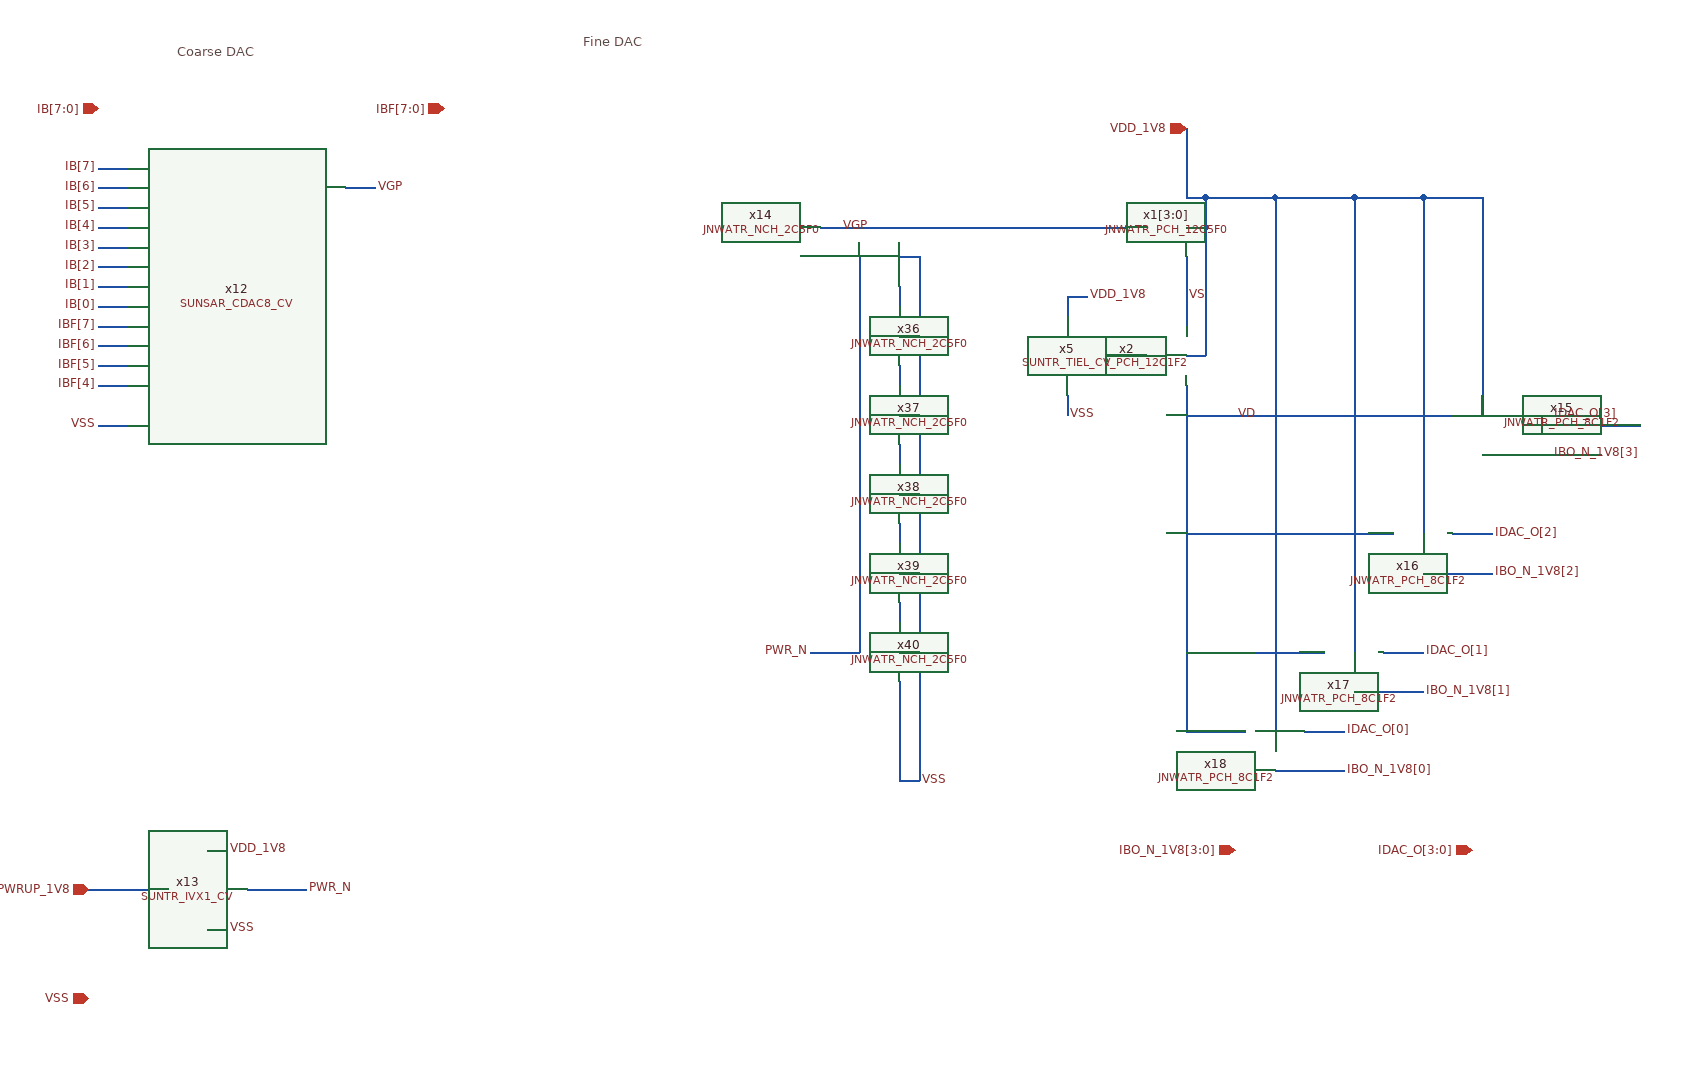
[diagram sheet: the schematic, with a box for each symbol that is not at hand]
v {xschem version=3.4.5 file_version=1.2
}
G {}
K {}
V {}
S {}
E {}
T {Coarse DAC} 1280 -1430 0 0 0.4 0.4 {}
T {Fine DAC} 1690 -1440 0 0 0.4 0.4 {}
N 2300 -1210 2300 -1140 {
lab=VS}
N 2300 -1110 2320 -1110 {
lab=VDD_1V8}
N 2320 -1240 2320 -1110 {
lab=VDD_1V8}
N 2300 -1240 2320 -1240 {
lab=VDD_1V8}
N 2320 -1270 2320 -1240 {
lab=VDD_1V8}
N 2300 -1270 2320 -1270 {
lab=VDD_1V8}
N 2300 -1330 2300 -1270 {
lab=VDD_1V8}
N 1930 -1240 2260 -1240 {
lab=VGP}
N 2300 -1080 2300 -900 {
lab=VD}
N 1310 -610 1330 -610 {
lab=VDD_1V8}
N 1310 -530 1330 -530 {
lab=VSS}
N 1250 -570 1270 -570 {
lab=PWRUP_1V8}
N 1190 -570 1250 -570 {
lab=PWRUP_1V8}
N 1350 -570 1410 -570 {
lab=PWR_N}
N 2390 -1270 2390 -730 {
lab=VDD_1V8}
N 2320 -1270 2390 -1270 {
lab=VDD_1V8}
N 2470 -1270 2470 -810 {
lab=VDD_1V8}
N 2390 -1270 2470 -1270 {
lab=VDD_1V8}
N 2470 -1270 2540 -1270 {
lab=VDD_1V8}
N 2600 -1270 2600 -1050 {
lab=VDD_1V8}
N 2540 -1270 2600 -1270 {
lab=VDD_1V8}
N 2300 -1050 2570 -1050 {
lab=VD}
N 2300 -900 2300 -730 {
lab=VD}
N 2300 -730 2360 -730 {
lab=VD}
N 2300 -810 2440 -810 {
lab=VD}
N 2300 -930 2510 -930 {
lab=VD}
N 2540 -1270 2540 -930 {
lab=VDD_1V8}
N 2630 -1050 2670 -1050 {
lab=IDAC_O[3]}
N 2570 -930 2610 -930 {
lab=IDAC_O[2]}
N 2500 -810 2540 -810 {
lab=IDAC_O[1]}
N 2420 -730 2460 -730 {
lab=IDAC_O[0]}
N 2390 -690 2460 -690 {
lab=IBO_N_1V8[0]}
N 2470 -770 2540 -770 {
lab=IBO_N_1V8[1]}
N 2540 -890 2610 -890 {
lab=IBO_N_1V8[2]}
N 2600 -1010 2670 -1010 {
lab=IBO_N_1V8[3]}
N 1200 -1160 1230 -1160 {
lab=IB[0]}
N 1200 -1180 1230 -1180 {
lab=IB[1]}
N 1200 -1200 1230 -1200 {
lab=IB[2]}
N 1200 -1220 1230 -1220 {
lab=IB[3]}
N 1200 -1240 1230 -1240 {
lab=IB[4]}
N 1200 -1260 1230 -1260 {
lab=IB[5]}
N 1200 -1280 1230 -1280 {
lab=IB[6]}
N 1200 -1300 1230 -1300 {
lab=IB[7]}
N 1450 -1280 1480 -1280 {
lab=VGP}
N 1200 -1040 1230 -1040 {
lab=VSS}
N 2660 -1040 2760 -1040 {
lab=IDAC_O[3]}
N 2660 -1050 2660 -1040 {
lab=IDAC_O[3]}
N 2300 -1340 2300 -1330 {
lab=VDD_1V8}
N 2010 -860 2010 -840 {
lab=#net1}
N 2010 -940 2010 -920 {
lab=#net2}
N 2010 -1020 2010 -1000 {
lab=#net3}
N 2010 -1100 2010 -1080 {
lab=#net4}
N 2010 -1180 2010 -1160 {
lab=#net5}
N 2010 -1210 2030 -1210 {
lab=VSS}
N 2030 -1210 2030 -740 {
lab=VSS}
N 2010 -810 2030 -810 {
lab=VSS}
N 2010 -890 2030 -890 {
lab=VSS}
N 2010 -970 2030 -970 {
lab=VSS}
N 2010 -1130 2030 -1130 {
lab=VSS}
N 1970 -1210 1970 -810 {
lab=PWR_N}
N 1920 -810 1970 -810 {
lab=PWR_N}
N 2010 -1050 2030 -1050 {
lab=VSS}
N 2220 -1110 2260 -1110 {
lab=#net6}
N 2180 -1170 2180 -1150 {
lab=VDD_1V8}
N 2180 -1170 2200 -1170 {
lab=VDD_1V8}
N 2180 -1070 2180 -1050 {
lab=VSS}
N 1200 -1140 1230 -1140 {
lab=IBF[7]}
N 1200 -1120 1230 -1120 {
lab=IBF[6]}
N 1200 -1100 1230 -1100 {
lab=IBF[5]}
N 1200 -1080 1230 -1080 {
lab=IBF[4]}
N 2010 -780 2010 -740 {
lab=VSS}
N 2030 -740 2030 -710 {
lab=VSS}
N 2010 -680 2030 -680 {
lab=VSS}
N 2030 -710 2030 -680 {
lab=VSS}
N 2010 -740 2010 -680 {
lab=VSS}
C {devices/ipin.sym} 2300 -1340 0 0 {name=p1 lab=VDD_1V8}
C {devices/ipin.sym} 1190 -460 0 0 {name=p2 lab=VSS}
C {devices/ipin.sym} 1190 -570 0 0 {name=p3 lab=PWRUP_1V8}
C {JNW_ATR_SKY130NM/JNWATR_PCH_12C5F0.sym} 2260 -1240 0 0 {name=x1[3:0]}
C {JNW_ATR_SKY130NM/JNWATR_PCH_12C1F2.sym} 2260 -1110 0 0 {name=x2 }
C {SUN_TR_SKY130NM/SUNTR_IVX1_CV.sym} 1270 -570 0 0 {name=x13 }
C {devices/lab_wire.sym} 1330 -610 0 1 {name=p29 sig_type=std_logic lab=VDD_1V8}
C {devices/lab_wire.sym} 1330 -530 0 1 {name=p30 sig_type=std_logic lab=VSS}
C {devices/lab_wire.sym} 2030 -680 0 1 {name=p31 sig_type=std_logic lab=VSS}
C {devices/lab_wire.sym} 1410 -570 0 1 {name=p33 sig_type=std_logic lab=PWR_N}
C {devices/iopin.sym} 2590 -610 0 0 {name=p35 lab=IDAC_O[3:0]}
C {JNW_ATR_SKY130NM/JNWATR_PCH_8C1F2.sym} 2600 -1010 3 0 {name=x15 }
C {JNW_ATR_SKY130NM/JNWATR_PCH_8C1F2.sym} 2540 -890 3 0 {name=x16 }
C {JNW_ATR_SKY130NM/JNWATR_PCH_8C1F2.sym} 2470 -770 3 0 {name=x17 }
C {JNW_ATR_SKY130NM/JNWATR_PCH_8C1F2.sym} 2390 -690 3 0 {name=x18 }
C {devices/lab_wire.sym} 2460 -730 0 1 {name=p36 sig_type=std_logic lab=IDAC_O[0]}
C {devices/lab_wire.sym} 2540 -810 0 1 {name=p37 sig_type=std_logic lab=IDAC_O[1]}
C {devices/lab_wire.sym} 2610 -930 0 1 {name=p38 sig_type=std_logic lab=IDAC_O[2]}
C {devices/lab_wire.sym} 2670 -1050 0 1 {name=p39 sig_type=std_logic lab=IDAC_O[3]}
C {devices/lab_wire.sym} 2460 -690 0 1 {name=p40 sig_type=std_logic lab=IBO_N_1V8[0]}
C {devices/lab_wire.sym} 2540 -770 0 1 {name=p41 sig_type=std_logic lab=IBO_N_1V8[1]}
C {devices/lab_wire.sym} 2610 -890 0 1 {name=p42 sig_type=std_logic lab=IBO_N_1V8[2]}
C {devices/lab_wire.sym} 2670 -1010 0 1 {name=p43 sig_type=std_logic lab=IBO_N_1V8[3]}
C {devices/ipin.sym} 1200 -1360 0 0 {name=p44 lab=IB[7:0]}
C {devices/ipin.sym} 2350 -610 0 0 {name=p45 lab=IBO_N_1V8[3:0]}
C {devices/lab_wire.sym} 2300 -1170 0 1 {name=p47 sig_type=std_logic lab=VS}
C {devices/lab_wire.sym} 2350 -1050 0 1 {name=p48 sig_type=std_logic lab=VD}
C {devices/lab_wire.sym} 1950 -1240 0 1 {name=p49 sig_type=std_logic lab=VGP}
C {devices/lab_wire.sym} 1200 -1160 0 0 {name=p46 sig_type=std_logic lab=IB[0]
}
C {devices/lab_wire.sym} 1200 -1180 0 0 {name=p66 sig_type=std_logic lab=IB[1]
}
C {devices/lab_wire.sym} 1200 -1200 0 0 {name=p67 sig_type=std_logic lab=IB[2]
}
C {devices/lab_wire.sym} 1200 -1220 0 0 {name=p68 sig_type=std_logic lab=IB[3]
}
C {devices/lab_wire.sym} 1200 -1240 0 0 {name=p69 sig_type=std_logic lab=IB[4]
}
C {devices/lab_wire.sym} 1200 -1260 0 0 {name=p70 sig_type=std_logic lab=IB[5]
}
C {devices/lab_wire.sym} 1200 -1280 0 0 {name=p71 sig_type=std_logic lab=IB[6]
}
C {devices/lab_wire.sym} 1200 -1300 0 0 {name=p72 sig_type=std_logic lab=IB[7]
}
C {devices/lab_wire.sym} 1480 -1280 0 1 {name=p73 sig_type=std_logic lab=VGP
}
C {devices/lab_wire.sym} 1200 -1040 0 0 {name=p74 sig_type=std_logic lab=VSS
}
C {SUN_SAR9B_SKY130NM/SUNSAR_CDAC8_CV.sym} 1250 -1300 0 0 {name=x12}
C {devices/ipin.sym} 1550 -1360 0 0 {name=p124 lab=IBF[7:0]}
C {devices/lab_wire.sym} 1920 -810 0 0 {name=p34 sig_type=std_logic lab=PWR_N}
C {JNW_ATR_SKY130NM/JNWATR_NCH_2C5F0.sym} 1970 -1210 0 0 {name=x14 }
C {JNW_ATR_SKY130NM/JNWATR_NCH_2C5F0.sym} 1970 -1130 0 0 {name=x36 }
C {JNW_ATR_SKY130NM/JNWATR_NCH_2C5F0.sym} 1970 -1050 0 0 {name=x37 }
C {JNW_ATR_SKY130NM/JNWATR_NCH_2C5F0.sym} 1970 -970 0 0 {name=x38 }
C {JNW_ATR_SKY130NM/JNWATR_NCH_2C5F0.sym} 1970 -890 0 0 {name=x39 }
C {JNW_ATR_SKY130NM/JNWATR_NCH_2C5F0.sym} 1970 -810 0 0 {name=x40 }
C {SUN_TR_SKY130NM/SUNTR_TIEL_CV.sym} 2180 -1070 0 0 {name=x5 }
C {devices/lab_wire.sym} 2200 -1170 0 1 {name=p125 sig_type=std_logic lab=VDD_1V8}
C {devices/lab_wire.sym} 2180 -1050 0 1 {name=p126 sig_type=std_logic lab=VSS}
C {devices/lab_wire.sym} 1200 -1140 0 0 {name=p4 sig_type=std_logic lab=IBF[7]
}
C {devices/lab_wire.sym} 1200 -1120 0 0 {name=p5 sig_type=std_logic lab=IBF[6]
}
C {devices/lab_wire.sym} 1200 -1100 0 0 {name=p6 sig_type=std_logic lab=IBF[5]
}
C {devices/lab_wire.sym} 1200 -1080 0 0 {name=p7 sig_type=std_logic lab=IBF[4]
}
